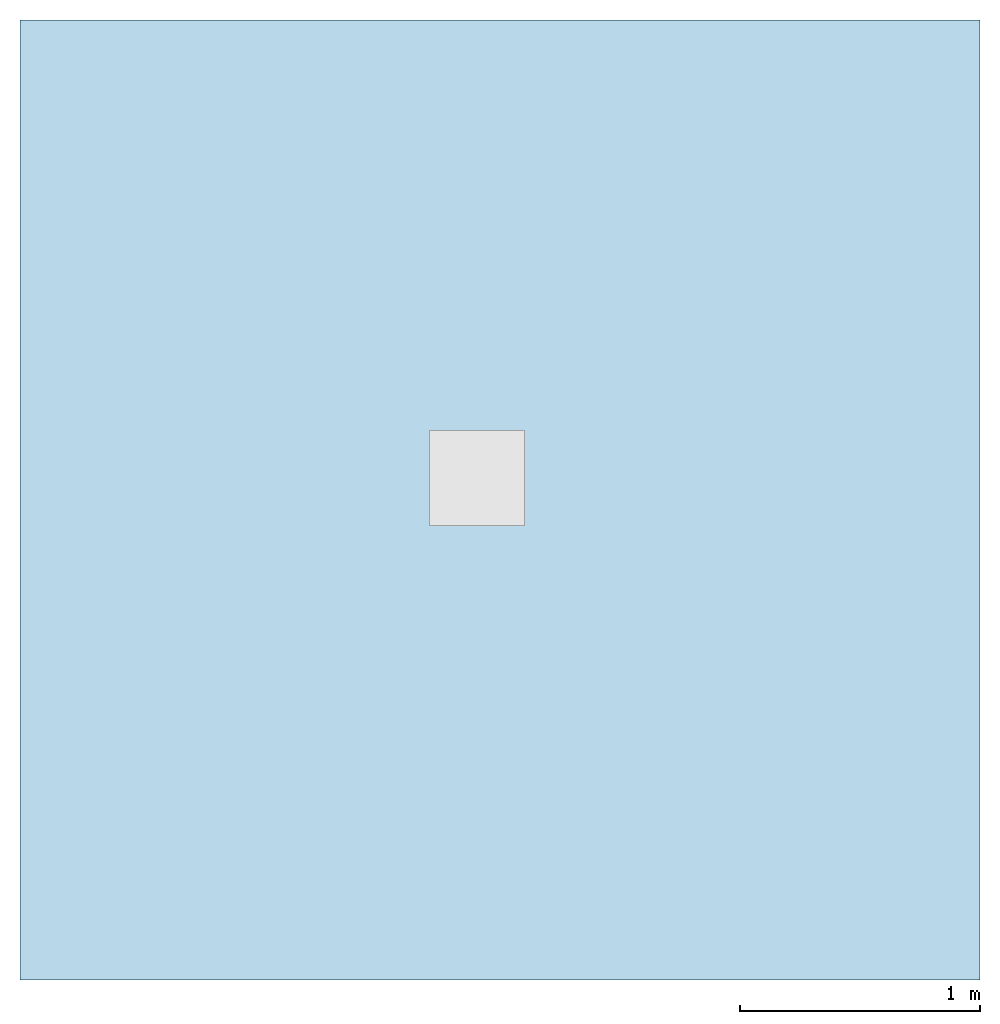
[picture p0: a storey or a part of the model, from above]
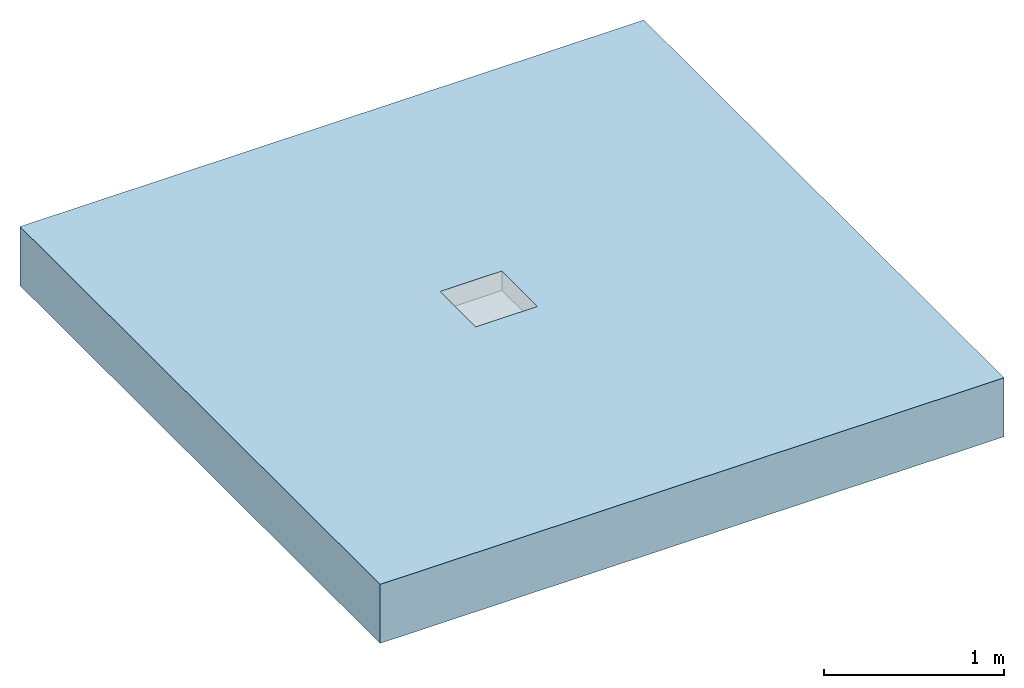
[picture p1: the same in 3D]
Properties of the parts of a building model (IFC2X3)

# File
Description: ViewDefinition [CoordinationView]
File name: Project Number
Time: 2014-06-06T10:53:38
Written by: The EXPRESS Data Manager Version 5.01.0100.02.64mod : 6 Jun 2012
Made in: 20130308_1515(x64) - Exporter 2014.0.2013.0308 - Default UI
Comment: STEP Physical File produced by: The EXPRESS Data Manager Version 5.01.0100.02.64mod : 6 Jun 2012 * Module: EDMstepFileFactory/EDMstandAlone * Creation date: Fri Jun 06 10:53:38 2014 * Host: IN-BLR-PC-0010 * Database: C:\Users\palleri\AppData\Local\Temp\{905EF42F-539A-4CC5-B409-75EFCE142E62}\ifc * Database version: 5507 * Database creation date: Fri Jun 06 10:53:37 2014 * Schema: IFC2X3 * Model: DataRepository.ifc * Model creation date: Fri Jun 06 10:53:38 2014 * Header model: DataRepository.ifc_HeaderModel * Header model creation date: Fri Jun 06 10:53:38 2014 * EDMuser: sdai-user * EDMgroup: sdai-group * License ID and type: 5605 : Permanent license. Expiry date: * EDMstepFileFactory options: 020000

# IfcProject, Project Number
LongName: Project Name; Phase: Project Status

# IfcSite, Default
RefLatitude: 42, 21, 30, 344238; RefLongitude: -71, -3, -35, -194702; RefElevation: 0 mm

# IfcBuilding
Pset_BuildingCommon - NumberOfStoreys: 1
Other - Project Name: Project Name; Client Name: Owner; Project Address: ## Street City, State Zip; Project Status: Project Status; Project Issue Date: Issue Date; Project Number: Project Number

# IfcBuildingStorey, Level 1
LongName: Level 1; Elevation: 0 mm
Graphics - Symbol at End 1 Default: no; Line Pattern: Center; Color: 0; Symbol at End 2 Default: yes; Line Weight: 1; Symbol: M_Level Head - Circle: M_Level Head - Circle
Constraints - Elevation Base: Project Base Point; Elevation: 0 mm
Dimensions - Computation Height: 0 mm
Identity Data - Name: Level 1; Structural: no; Building Story: yes

# IfcFlowTerminal: 38801 - Access Frame - Adjustable Height - Invert Depth 75/105mm, ACO Freedeck Access Frame & Drain Duct (Accessories part 1) V1.27 - GS:38801 - Access Frame - Adjustable Height - Invert Depth 75/105mm:276243
In: Level 1
Material: Galvanized Steel
Materials and Finishes - Material: Galvanized Steel
Construction - 38687_Access Frame Extension_Galvanized Steel_Invert Depth 75mm: no; 38685_Access Frame Extension_Galvanized Steel_Invert Depth 50mm: yes; 36754_Access Grating_Mesh Grating_Galvanized Steel: yes
Dimensions - Base Height: 50 mm; Drainage Duct – Level below FFL: 30 mm; Height for Adjustable Access Frame: 105 mm; Total Height: 134 mm; Top Void Height Start: -80 mm; Access Frame Extension Position Height: 0 mm; Top Void Height End: -30 mm; Drain Duct End: -100 mm; Grating End: -20 mm; Grating Start: 0 mm
Other - Access Frame Extension_Invert Depth 50mm: yes; Extension Removal Void: -2 mm; Access Frame Extension_Invert Depth 75mm: no; Adjustable Access Frame Position Height: 105 mm; Fixed Access Frame Position Height: 80 mm; Access Frame Extension Height: 50 mm; Access Frame Extension: yes; Drain Duct Vertical Height: 5000 mm; Grating: yes; Access Frame Adjustable Height: yes; Drain Duct: no; Access Frame Fixed Height: no; Top void Size: 397 mm
Constraints - Level: Level: Level 1; Moves With Nearby Elements: no
Phasing - Phase Created: New Construction
Identity Data - Mark: 14; Watermark1: This file is the property of ACO Technologies PLC; Manufacturer: ACO Building Drainage; E-mail Technical: abdtechnical@aco.co.uk; Address: ACO Business Centre, Caxton Road, Bedford, MK41 0LF; Watermarked With: BIM Manager Premium Suite; Telephone: +44 (0)1462 816666; Watermark2: This file is water marked and users are prohibited to reproduce, adapt, distribute this information; Website: www.acobd.com; Fax: +44 (0)1462 851490; Watermarked By: www.acobd.com; E-mail Sales: abdcommercial@aco.co.uk
Pset_ManufacturerTypeInformation - Manufacturer: ACO Building Drainage
Model Properties - Access Grating Product Code 36760: N/A; Access Frame Extension Product Code 38687: Load Class A15 - Access Frame Extension - Galvanized Steel - Invert Depth 75mm - 1.9kg; Access Grating Product Code 36754: Load Class A15 - Mesh Grating - 14mm x 30mm Mesh - Galvanized Steel - 3.5kg; Access Frame Extension Product Code 38685: Load Class A15 - Access Frame Extension - Galvanized Steel - Invert Depth 50mm - 1.3kg; Access Frame Extension Product Code 38686: N/A; Access Frame Extension Product Code 38688: N/A
General - Product Code: 38801; Installation Guidelines: X:\Electronic Literature\ABD Electronic Literature\Roof and Balcony Drainage\ACO Freedeck Brochure.pdf; Weight (Kg): 3.1kg; Maintenance Guidelines: X:\Electronic Literature\ABD Electronic Literature\Roof and Balcony Drainage\ACO Freedeck Brochure.pdf; Price: POA - contact ACO; Dimensions (LxWxH): 400 x 400 x 75/105; Product Type: Linear Deck Drainage System; Load Class: A15; NBS Specification: NBS Section R10 Gravity Rainwater Drainage Systems, Subsection 365; Channel Recyclable: Fully recyclable; Product Standard: BS EN 1433:2002, CE marked; Product Description: ACO Freedeck Access Frame - Adjustable; Channel Recycled Material Content: 25 - 30 %; Product Range: ACO Freedeck; Channel Material: Hot Dipped Galvanised Steel; Channel Colour: Galvanised

# IfcOpeningElement: Recess (2)
In: Level 1
Dimensions - Area: 16 m2; Thickness: 400 mm; Volume: 6.37875 m3; Perimeter: 16000 mm
Constraints - Related to Mass: no; Height Offset From Level: 0 mm; Level: Level: Level 1; Room Bounding: yes
Structural - Structural: no; Enable Analytical Model: no
Phasing - Phase Created: New Construction
Analytical Properties - Absorptance: 0.1; Thermal Resistance (R): 0.382409; Heat Transfer Coefficient (U): 2.615; Roughness: 1; Thermal mass: 604440
Graphics - Coarse Scale Fill Color: 0
Materials and Finishes - Structural Material: Concrete, Broom Finish
Construction - Function: Interior; Default Thickness: 400 mm

# IfcSlab: Floor:Generic Floor - 400mm, Floor:Generic Floor - 400mm:193825
In: Level 1
PredefinedType: FLOOR; Material: Concrete, Broom Finish 400 mm
Dimensions - Area: 16 m2; Thickness: 400 mm; Volume: 6.37875 m3; Perimeter: 16000 mm
Constraints - Related to Mass: no; Height Offset From Level: 0 mm; Level: Level: Level 1; Room Bounding: yes
Structural - Structural: no; Enable Analytical Model: no
Phasing - Phase Created: New Construction
Pset_SlabCommon - Reference: Generic Floor - 400mm; IsExternal: no; LoadBearing: yes; ThermalTransmittance: 2.615 kg/K/s3
Analytical Properties - Absorptance: 0.1; Thermal Resistance (R): 0.382409; Heat Transfer Coefficient (U): 2.615; Roughness: 1; Thermal mass: 604440
Graphics - Coarse Scale Fill Color: 0
Materials and Finishes - Structural Material: Concrete, Broom Finish
Construction - Function: Interior; Default Thickness: 400 mm
